VERSION 5.7 ;
  NOWIREEXTENSIONATPIN ON ;
  DIVIDERCHAR "/" ;
  BUSBITCHARS "[]" ;
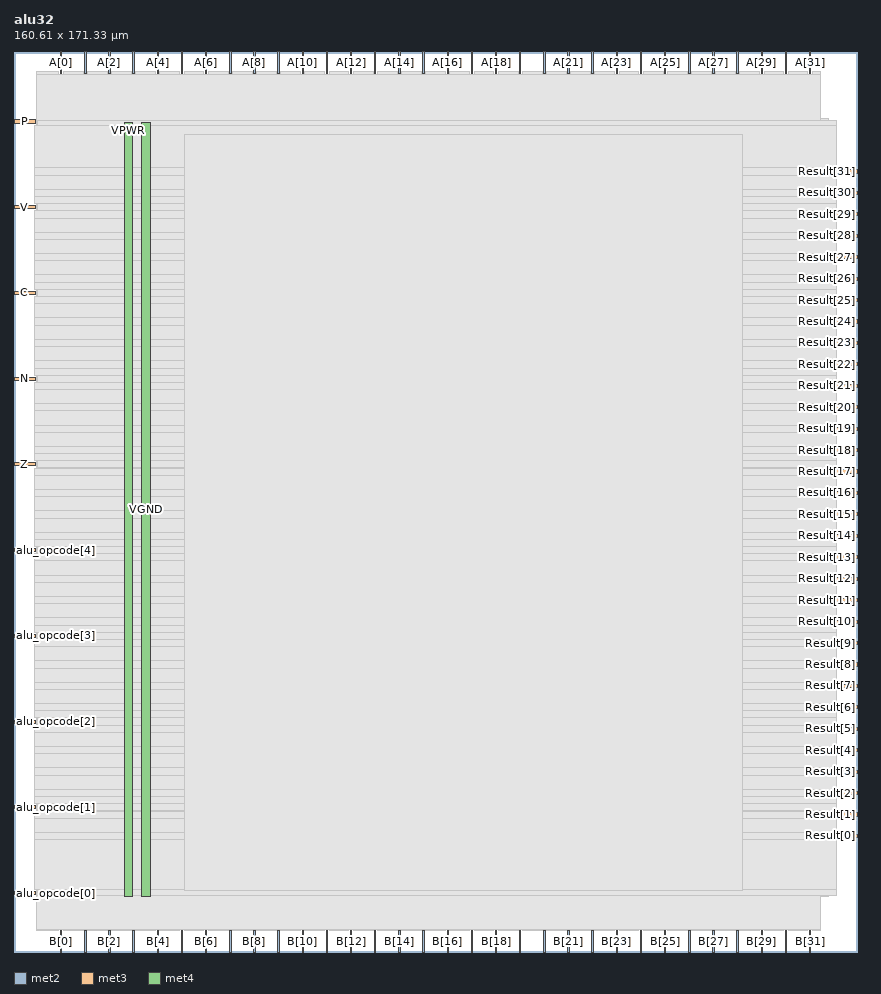
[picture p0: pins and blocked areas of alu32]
MACRO alu32
  CLASS BLOCK ;
  FOREIGN alu32 ;
  ORIGIN 0.000 0.000 ;
  SIZE 160.610 BY 171.330 ;
  PIN A[0]
    DIRECTION INPUT ;
    USE SIGNAL ;
    ANTENNAGATEAREA 0.213000 ;
    PORT
      LAYER met2 ;
        RECT 8.830 167.330 9.110 171.330 ;
    END
  END A[0]
  PIN A[10]
    DIRECTION INPUT ;
    USE SIGNAL ;
    ANTENNAGATEAREA 0.196500 ;
    PORT
      LAYER met2 ;
        RECT 54.830 167.330 55.110 171.330 ;
    END
  END A[10]
  PIN A[11]
    DIRECTION INPUT ;
    USE SIGNAL ;
    ANTENNAGATEAREA 0.196500 ;
    PORT
      LAYER met2 ;
        RECT 59.430 167.330 59.710 171.330 ;
    END
  END A[11]
  PIN A[12]
    DIRECTION INPUT ;
    USE SIGNAL ;
    ANTENNAGATEAREA 0.196500 ;
    PORT
      LAYER met2 ;
        RECT 64.030 167.330 64.310 171.330 ;
    END
  END A[12]
  PIN A[13]
    DIRECTION INPUT ;
    USE SIGNAL ;
    ANTENNAGATEAREA 0.196500 ;
    PORT
      LAYER met2 ;
        RECT 68.630 167.330 68.910 171.330 ;
    END
  END A[13]
  PIN A[14]
    DIRECTION INPUT ;
    USE SIGNAL ;
    ANTENNAGATEAREA 0.196500 ;
    PORT
      LAYER met2 ;
        RECT 73.230 167.330 73.510 171.330 ;
    END
  END A[14]
  PIN A[15]
    DIRECTION INPUT ;
    USE SIGNAL ;
    ANTENNAGATEAREA 0.196500 ;
    PORT
      LAYER met2 ;
        RECT 77.830 167.330 78.110 171.330 ;
    END
  END A[15]
  PIN A[16]
    DIRECTION INPUT ;
    USE SIGNAL ;
    ANTENNAGATEAREA 0.159000 ;
    PORT
      LAYER met2 ;
        RECT 82.430 167.330 82.710 171.330 ;
    END
  END A[16]
  PIN A[17]
    DIRECTION INPUT ;
    USE SIGNAL ;
    ANTENNAGATEAREA 0.159000 ;
    PORT
      LAYER met2 ;
        RECT 87.030 167.330 87.310 171.330 ;
    END
  END A[17]
  PIN A[18]
    DIRECTION INPUT ;
    USE SIGNAL ;
    ANTENNAGATEAREA 0.196500 ;
    PORT
      LAYER met2 ;
        RECT 91.630 167.330 91.910 171.330 ;
    END
  END A[18]
  PIN A[19]
    DIRECTION INPUT ;
    USE SIGNAL ;
    ANTENNAGATEAREA 0.196500 ;
    PORT
      LAYER met2 ;
        RECT 96.230 167.330 96.510 171.330 ;
    END
  END A[19]
  PIN A[1]
    DIRECTION INPUT ;
    USE SIGNAL ;
    ANTENNAGATEAREA 0.196500 ;
    PORT
      LAYER met2 ;
        RECT 13.430 167.330 13.710 171.330 ;
    END
  END A[1]
  PIN A[20]
    DIRECTION INPUT ;
    USE SIGNAL ;
    ANTENNAGATEAREA 0.196500 ;
    PORT
      LAYER met2 ;
        RECT 100.830 167.330 101.110 171.330 ;
    END
  END A[20]
  PIN A[21]
    DIRECTION INPUT ;
    USE SIGNAL ;
    ANTENNAGATEAREA 0.196500 ;
    PORT
      LAYER met2 ;
        RECT 105.430 167.330 105.710 171.330 ;
    END
  END A[21]
  PIN A[22]
    DIRECTION INPUT ;
    USE SIGNAL ;
    ANTENNAGATEAREA 0.196500 ;
    PORT
      LAYER met2 ;
        RECT 110.030 167.330 110.310 171.330 ;
    END
  END A[22]
  PIN A[23]
    DIRECTION INPUT ;
    USE SIGNAL ;
    ANTENNAGATEAREA 0.196500 ;
    PORT
      LAYER met2 ;
        RECT 114.630 167.330 114.910 171.330 ;
    END
  END A[23]
  PIN A[24]
    DIRECTION INPUT ;
    USE SIGNAL ;
    ANTENNAGATEAREA 0.196500 ;
    PORT
      LAYER met2 ;
        RECT 119.230 167.330 119.510 171.330 ;
    END
  END A[24]
  PIN A[25]
    DIRECTION INPUT ;
    USE SIGNAL ;
    ANTENNAGATEAREA 0.196500 ;
    PORT
      LAYER met2 ;
        RECT 123.830 167.330 124.110 171.330 ;
    END
  END A[25]
  PIN A[26]
    DIRECTION INPUT ;
    USE SIGNAL ;
    ANTENNAGATEAREA 0.196500 ;
    PORT
      LAYER met2 ;
        RECT 128.430 167.330 128.710 171.330 ;
    END
  END A[26]
  PIN A[27]
    DIRECTION INPUT ;
    USE SIGNAL ;
    ANTENNAGATEAREA 0.196500 ;
    PORT
      LAYER met2 ;
        RECT 133.030 167.330 133.310 171.330 ;
    END
  END A[27]
  PIN A[28]
    DIRECTION INPUT ;
    USE SIGNAL ;
    ANTENNAGATEAREA 0.196500 ;
    PORT
      LAYER met2 ;
        RECT 137.630 167.330 137.910 171.330 ;
    END
  END A[28]
  PIN A[29]
    DIRECTION INPUT ;
    USE SIGNAL ;
    ANTENNAGATEAREA 0.196500 ;
    PORT
      LAYER met2 ;
        RECT 142.230 167.330 142.510 171.330 ;
    END
  END A[29]
  PIN A[2]
    DIRECTION INPUT ;
    USE SIGNAL ;
    ANTENNAGATEAREA 0.196500 ;
    PORT
      LAYER met2 ;
        RECT 18.030 167.330 18.310 171.330 ;
    END
  END A[2]
  PIN A[30]
    DIRECTION INPUT ;
    USE SIGNAL ;
    ANTENNAGATEAREA 0.196500 ;
    PORT
      LAYER met2 ;
        RECT 146.830 167.330 147.110 171.330 ;
    END
  END A[30]
  PIN A[31]
    DIRECTION INPUT ;
    USE SIGNAL ;
    ANTENNAGATEAREA 0.196500 ;
    PORT
      LAYER met2 ;
        RECT 151.430 167.330 151.710 171.330 ;
    END
  END A[31]
  PIN A[3]
    DIRECTION INPUT ;
    USE SIGNAL ;
    ANTENNAGATEAREA 0.196500 ;
    PORT
      LAYER met2 ;
        RECT 22.630 167.330 22.910 171.330 ;
    END
  END A[3]
  PIN A[4]
    DIRECTION INPUT ;
    USE SIGNAL ;
    ANTENNAGATEAREA 0.196500 ;
    PORT
      LAYER met2 ;
        RECT 27.230 167.330 27.510 171.330 ;
    END
  END A[4]
  PIN A[5]
    DIRECTION INPUT ;
    USE SIGNAL ;
    ANTENNAGATEAREA 0.196500 ;
    PORT
      LAYER met2 ;
        RECT 31.830 167.330 32.110 171.330 ;
    END
  END A[5]
  PIN A[6]
    DIRECTION INPUT ;
    USE SIGNAL ;
    ANTENNAGATEAREA 0.196500 ;
    PORT
      LAYER met2 ;
        RECT 36.430 167.330 36.710 171.330 ;
    END
  END A[6]
  PIN A[7]
    DIRECTION INPUT ;
    USE SIGNAL ;
    ANTENNAGATEAREA 0.196500 ;
    PORT
      LAYER met2 ;
        RECT 41.030 167.330 41.310 171.330 ;
    END
  END A[7]
  PIN A[8]
    DIRECTION INPUT ;
    USE SIGNAL ;
    ANTENNAGATEAREA 0.196500 ;
    PORT
      LAYER met2 ;
        RECT 45.630 167.330 45.910 171.330 ;
    END
  END A[8]
  PIN A[9]
    DIRECTION INPUT ;
    USE SIGNAL ;
    ANTENNAGATEAREA 0.196500 ;
    PORT
      LAYER met2 ;
        RECT 50.230 167.330 50.510 171.330 ;
    END
  END A[9]
  PIN B[0]
    DIRECTION INPUT ;
    USE SIGNAL ;
    ANTENNAGATEAREA 0.247500 ;
    PORT
      LAYER met2 ;
        RECT 8.830 0.000 9.110 4.000 ;
    END
  END B[0]
  PIN B[10]
    DIRECTION INPUT ;
    USE SIGNAL ;
    ANTENNAGATEAREA 0.196500 ;
    PORT
      LAYER met2 ;
        RECT 54.830 0.000 55.110 4.000 ;
    END
  END B[10]
  PIN B[11]
    DIRECTION INPUT ;
    USE SIGNAL ;
    ANTENNAGATEAREA 0.126000 ;
    PORT
      LAYER met2 ;
        RECT 59.430 0.000 59.710 4.000 ;
    END
  END B[11]
  PIN B[12]
    DIRECTION INPUT ;
    USE SIGNAL ;
    ANTENNAGATEAREA 0.126000 ;
    PORT
      LAYER met2 ;
        RECT 64.030 0.000 64.310 4.000 ;
    END
  END B[12]
  PIN B[13]
    DIRECTION INPUT ;
    USE SIGNAL ;
    ANTENNAGATEAREA 0.196500 ;
    PORT
      LAYER met2 ;
        RECT 68.630 0.000 68.910 4.000 ;
    END
  END B[13]
  PIN B[14]
    DIRECTION INPUT ;
    USE SIGNAL ;
    ANTENNAGATEAREA 0.213000 ;
    PORT
      LAYER met2 ;
        RECT 73.230 0.000 73.510 4.000 ;
    END
  END B[14]
  PIN B[15]
    DIRECTION INPUT ;
    USE SIGNAL ;
    ANTENNAGATEAREA 0.196500 ;
    PORT
      LAYER met2 ;
        RECT 77.830 0.000 78.110 4.000 ;
    END
  END B[15]
  PIN B[16]
    DIRECTION INPUT ;
    USE SIGNAL ;
    ANTENNAGATEAREA 0.126000 ;
    PORT
      LAYER met2 ;
        RECT 82.430 0.000 82.710 4.000 ;
    END
  END B[16]
  PIN B[17]
    DIRECTION INPUT ;
    USE SIGNAL ;
    ANTENNAGATEAREA 0.196500 ;
    PORT
      LAYER met2 ;
        RECT 87.030 0.000 87.310 4.000 ;
    END
  END B[17]
  PIN B[18]
    DIRECTION INPUT ;
    USE SIGNAL ;
    ANTENNAGATEAREA 0.213000 ;
    PORT
      LAYER met2 ;
        RECT 91.630 0.000 91.910 4.000 ;
    END
  END B[18]
  PIN B[19]
    DIRECTION INPUT ;
    USE SIGNAL ;
    ANTENNAGATEAREA 0.213000 ;
    PORT
      LAYER met2 ;
        RECT 96.230 0.000 96.510 4.000 ;
    END
  END B[19]
  PIN B[1]
    DIRECTION INPUT ;
    USE SIGNAL ;
    ANTENNAGATEAREA 0.213000 ;
    PORT
      LAYER met2 ;
        RECT 13.430 0.000 13.710 4.000 ;
    END
  END B[1]
  PIN B[20]
    DIRECTION INPUT ;
    USE SIGNAL ;
    ANTENNAGATEAREA 0.196500 ;
    PORT
      LAYER met2 ;
        RECT 100.830 0.000 101.110 4.000 ;
    END
  END B[20]
  PIN B[21]
    DIRECTION INPUT ;
    USE SIGNAL ;
    ANTENNAGATEAREA 0.213000 ;
    PORT
      LAYER met2 ;
        RECT 105.430 0.000 105.710 4.000 ;
    END
  END B[21]
  PIN B[22]
    DIRECTION INPUT ;
    USE SIGNAL ;
    ANTENNAGATEAREA 0.126000 ;
    PORT
      LAYER met2 ;
        RECT 110.030 0.000 110.310 4.000 ;
    END
  END B[22]
  PIN B[23]
    DIRECTION INPUT ;
    USE SIGNAL ;
    ANTENNAGATEAREA 0.213000 ;
    PORT
      LAYER met2 ;
        RECT 114.630 0.000 114.910 4.000 ;
    END
  END B[23]
  PIN B[24]
    DIRECTION INPUT ;
    USE SIGNAL ;
    ANTENNAGATEAREA 0.213000 ;
    PORT
      LAYER met2 ;
        RECT 119.230 0.000 119.510 4.000 ;
    END
  END B[24]
  PIN B[25]
    DIRECTION INPUT ;
    USE SIGNAL ;
    ANTENNAGATEAREA 0.196500 ;
    PORT
      LAYER met2 ;
        RECT 123.830 0.000 124.110 4.000 ;
    END
  END B[25]
  PIN B[26]
    DIRECTION INPUT ;
    USE SIGNAL ;
    ANTENNAGATEAREA 0.126000 ;
    PORT
      LAYER met2 ;
        RECT 128.430 0.000 128.710 4.000 ;
    END
  END B[26]
  PIN B[27]
    DIRECTION INPUT ;
    USE SIGNAL ;
    ANTENNAGATEAREA 0.213000 ;
    PORT
      LAYER met2 ;
        RECT 133.030 0.000 133.310 4.000 ;
    END
  END B[27]
  PIN B[28]
    DIRECTION INPUT ;
    USE SIGNAL ;
    ANTENNAGATEAREA 0.213000 ;
    PORT
      LAYER met2 ;
        RECT 137.630 0.000 137.910 4.000 ;
    END
  END B[28]
  PIN B[29]
    DIRECTION INPUT ;
    USE SIGNAL ;
    ANTENNAGATEAREA 0.213000 ;
    PORT
      LAYER met2 ;
        RECT 142.230 0.000 142.510 4.000 ;
    END
  END B[29]
  PIN B[2]
    DIRECTION INPUT ;
    USE SIGNAL ;
    ANTENNAGATEAREA 0.196500 ;
    PORT
      LAYER met2 ;
        RECT 18.030 0.000 18.310 4.000 ;
    END
  END B[2]
  PIN B[30]
    DIRECTION INPUT ;
    USE SIGNAL ;
    ANTENNAGATEAREA 0.213000 ;
    PORT
      LAYER met2 ;
        RECT 146.830 0.000 147.110 4.000 ;
    END
  END B[30]
  PIN B[31]
    DIRECTION INPUT ;
    USE SIGNAL ;
    ANTENNAGATEAREA 0.213000 ;
    PORT
      LAYER met2 ;
        RECT 151.430 0.000 151.710 4.000 ;
    END
  END B[31]
  PIN B[3]
    DIRECTION INPUT ;
    USE SIGNAL ;
    ANTENNAGATEAREA 0.196500 ;
    PORT
      LAYER met2 ;
        RECT 22.630 0.000 22.910 4.000 ;
    END
  END B[3]
  PIN B[4]
    DIRECTION INPUT ;
    USE SIGNAL ;
    ANTENNAGATEAREA 0.196500 ;
    PORT
      LAYER met2 ;
        RECT 27.230 0.000 27.510 4.000 ;
    END
  END B[4]
  PIN B[5]
    DIRECTION INPUT ;
    USE SIGNAL ;
    ANTENNAGATEAREA 0.196500 ;
    PORT
      LAYER met2 ;
        RECT 31.830 0.000 32.110 4.000 ;
    END
  END B[5]
  PIN B[6]
    DIRECTION INPUT ;
    USE SIGNAL ;
    ANTENNAGATEAREA 0.126000 ;
    PORT
      LAYER met2 ;
        RECT 36.430 0.000 36.710 4.000 ;
    END
  END B[6]
  PIN B[7]
    DIRECTION INPUT ;
    USE SIGNAL ;
    ANTENNAGATEAREA 0.196500 ;
    PORT
      LAYER met2 ;
        RECT 41.030 0.000 41.310 4.000 ;
    END
  END B[7]
  PIN B[8]
    DIRECTION INPUT ;
    USE SIGNAL ;
    ANTENNAGATEAREA 0.196500 ;
    PORT
      LAYER met2 ;
        RECT 45.630 0.000 45.910 4.000 ;
    END
  END B[8]
  PIN B[9]
    DIRECTION INPUT ;
    USE SIGNAL ;
    ANTENNAGATEAREA 0.126000 ;
    PORT
      LAYER met2 ;
        RECT 50.230 0.000 50.510 4.000 ;
    END
  END B[9]
  PIN C
    DIRECTION OUTPUT ;
    USE SIGNAL ;
    ANTENNADIFFAREA 1.336500 ;
    PORT
      LAYER met3 ;
        RECT 0.000 125.160 4.000 125.760 ;
    END
  END C
  PIN N
    DIRECTION OUTPUT ;
    USE SIGNAL ;
    ANTENNADIFFAREA 0.445500 ;
    PORT
      LAYER met3 ;
        RECT 0.000 108.840 4.000 109.440 ;
    END
  END N
  PIN P
    DIRECTION OUTPUT ;
    USE SIGNAL ;
    ANTENNADIFFAREA 1.336500 ;
    PORT
      LAYER met3 ;
        RECT 0.000 157.800 4.000 158.400 ;
    END
  END P
  PIN Result[0]
    DIRECTION OUTPUT ;
    USE SIGNAL ;
    ANTENNADIFFAREA 1.336500 ;
    PORT
      LAYER met3 ;
        RECT 156.610 21.800 160.610 22.400 ;
    END
  END Result[0]
  PIN Result[10]
    DIRECTION OUTPUT ;
    USE SIGNAL ;
    ANTENNADIFFAREA 0.891000 ;
    PORT
      LAYER met3 ;
        RECT 156.610 62.600 160.610 63.200 ;
    END
  END Result[10]
  PIN Result[11]
    DIRECTION OUTPUT ;
    USE SIGNAL ;
    ANTENNADIFFAREA 1.336500 ;
    PORT
      LAYER met3 ;
        RECT 156.610 66.680 160.610 67.280 ;
    END
  END Result[11]
  PIN Result[12]
    DIRECTION OUTPUT ;
    USE SIGNAL ;
    ANTENNADIFFAREA 0.795200 ;
    PORT
      LAYER met3 ;
        RECT 156.610 70.760 160.610 71.360 ;
    END
  END Result[12]
  PIN Result[13]
    DIRECTION OUTPUT ;
    USE SIGNAL ;
    ANTENNADIFFAREA 1.336500 ;
    PORT
      LAYER met3 ;
        RECT 156.610 74.840 160.610 75.440 ;
    END
  END Result[13]
  PIN Result[14]
    DIRECTION OUTPUT ;
    USE SIGNAL ;
    ANTENNADIFFAREA 1.336500 ;
    PORT
      LAYER met3 ;
        RECT 156.610 78.920 160.610 79.520 ;
    END
  END Result[14]
  PIN Result[15]
    DIRECTION OUTPUT ;
    USE SIGNAL ;
    ANTENNADIFFAREA 1.336500 ;
    PORT
      LAYER met3 ;
        RECT 156.610 83.000 160.610 83.600 ;
    END
  END Result[15]
  PIN Result[16]
    DIRECTION OUTPUT ;
    USE SIGNAL ;
    ANTENNADIFFAREA 1.336500 ;
    PORT
      LAYER met3 ;
        RECT 156.610 87.080 160.610 87.680 ;
    END
  END Result[16]
  PIN Result[17]
    DIRECTION OUTPUT ;
    USE SIGNAL ;
    ANTENNADIFFAREA 1.336500 ;
    PORT
      LAYER met3 ;
        RECT 156.610 91.160 160.610 91.760 ;
    END
  END Result[17]
  PIN Result[18]
    DIRECTION OUTPUT ;
    USE SIGNAL ;
    ANTENNADIFFAREA 1.336500 ;
    PORT
      LAYER met3 ;
        RECT 156.610 95.240 160.610 95.840 ;
    END
  END Result[18]
  PIN Result[19]
    DIRECTION OUTPUT ;
    USE SIGNAL ;
    ANTENNADIFFAREA 1.336500 ;
    PORT
      LAYER met3 ;
        RECT 156.610 99.320 160.610 99.920 ;
    END
  END Result[19]
  PIN Result[1]
    DIRECTION OUTPUT ;
    USE SIGNAL ;
    ANTENNADIFFAREA 0.445500 ;
    PORT
      LAYER met3 ;
        RECT 156.610 25.880 160.610 26.480 ;
    END
  END Result[1]
  PIN Result[20]
    DIRECTION OUTPUT ;
    USE SIGNAL ;
    ANTENNADIFFAREA 1.336500 ;
    PORT
      LAYER met3 ;
        RECT 156.610 103.400 160.610 104.000 ;
    END
  END Result[20]
  PIN Result[21]
    DIRECTION OUTPUT ;
    USE SIGNAL ;
    ANTENNADIFFAREA 1.336500 ;
    PORT
      LAYER met3 ;
        RECT 156.610 107.480 160.610 108.080 ;
    END
  END Result[21]
  PIN Result[22]
    DIRECTION OUTPUT ;
    USE SIGNAL ;
    ANTENNADIFFAREA 1.336500 ;
    PORT
      LAYER met3 ;
        RECT 156.610 111.560 160.610 112.160 ;
    END
  END Result[22]
  PIN Result[23]
    DIRECTION OUTPUT ;
    USE SIGNAL ;
    ANTENNADIFFAREA 1.336500 ;
    PORT
      LAYER met3 ;
        RECT 156.610 115.640 160.610 116.240 ;
    END
  END Result[23]
  PIN Result[24]
    DIRECTION OUTPUT ;
    USE SIGNAL ;
    ANTENNADIFFAREA 1.782000 ;
    PORT
      LAYER met3 ;
        RECT 156.610 119.720 160.610 120.320 ;
    END
  END Result[24]
  PIN Result[25]
    DIRECTION OUTPUT ;
    USE SIGNAL ;
    ANTENNADIFFAREA 1.336500 ;
    PORT
      LAYER met3 ;
        RECT 156.610 123.800 160.610 124.400 ;
    END
  END Result[25]
  PIN Result[26]
    DIRECTION OUTPUT ;
    USE SIGNAL ;
    ANTENNADIFFAREA 1.782000 ;
    PORT
      LAYER met3 ;
        RECT 156.610 127.880 160.610 128.480 ;
    END
  END Result[26]
  PIN Result[27]
    DIRECTION OUTPUT ;
    USE SIGNAL ;
    ANTENNADIFFAREA 1.336500 ;
    PORT
      LAYER met3 ;
        RECT 156.610 131.960 160.610 132.560 ;
    END
  END Result[27]
  PIN Result[28]
    DIRECTION OUTPUT ;
    USE SIGNAL ;
    ANTENNADIFFAREA 1.336500 ;
    PORT
      LAYER met3 ;
        RECT 156.610 136.040 160.610 136.640 ;
    END
  END Result[28]
  PIN Result[29]
    DIRECTION OUTPUT ;
    USE SIGNAL ;
    ANTENNADIFFAREA 1.336500 ;
    PORT
      LAYER met3 ;
        RECT 156.610 140.120 160.610 140.720 ;
    END
  END Result[29]
  PIN Result[2]
    DIRECTION OUTPUT ;
    USE SIGNAL ;
    ANTENNADIFFAREA 1.336500 ;
    PORT
      LAYER met3 ;
        RECT 156.610 29.960 160.610 30.560 ;
    END
  END Result[2]
  PIN Result[30]
    DIRECTION OUTPUT ;
    USE SIGNAL ;
    ANTENNADIFFAREA 1.336500 ;
    PORT
      LAYER met3 ;
        RECT 156.610 144.200 160.610 144.800 ;
    END
  END Result[30]
  PIN Result[31]
    DIRECTION OUTPUT ;
    USE SIGNAL ;
    ANTENNADIFFAREA 1.336500 ;
    PORT
      LAYER met3 ;
        RECT 156.610 148.280 160.610 148.880 ;
    END
  END Result[31]
  PIN Result[3]
    DIRECTION OUTPUT ;
    USE SIGNAL ;
    ANTENNADIFFAREA 0.795200 ;
    PORT
      LAYER met3 ;
        RECT 156.610 34.040 160.610 34.640 ;
    END
  END Result[3]
  PIN Result[4]
    DIRECTION OUTPUT ;
    USE SIGNAL ;
    ANTENNADIFFAREA 0.445500 ;
    PORT
      LAYER met3 ;
        RECT 156.610 38.120 160.610 38.720 ;
    END
  END Result[4]
  PIN Result[5]
    DIRECTION OUTPUT ;
    USE SIGNAL ;
    ANTENNADIFFAREA 0.445500 ;
    PORT
      LAYER met3 ;
        RECT 156.610 42.200 160.610 42.800 ;
    END
  END Result[5]
  PIN Result[6]
    DIRECTION OUTPUT ;
    USE SIGNAL ;
    ANTENNADIFFAREA 0.445500 ;
    PORT
      LAYER met3 ;
        RECT 156.610 46.280 160.610 46.880 ;
    END
  END Result[6]
  PIN Result[7]
    DIRECTION OUTPUT ;
    USE SIGNAL ;
    ANTENNADIFFAREA 0.445500 ;
    PORT
      LAYER met3 ;
        RECT 156.610 50.360 160.610 50.960 ;
    END
  END Result[7]
  PIN Result[8]
    DIRECTION OUTPUT ;
    USE SIGNAL ;
    ANTENNADIFFAREA 0.795200 ;
    PORT
      LAYER met3 ;
        RECT 156.610 54.440 160.610 55.040 ;
    END
  END Result[8]
  PIN Result[9]
    DIRECTION OUTPUT ;
    USE SIGNAL ;
    ANTENNADIFFAREA 1.336500 ;
    PORT
      LAYER met3 ;
        RECT 156.610 58.520 160.610 59.120 ;
    END
  END Result[9]
  PIN V
    DIRECTION OUTPUT ;
    USE SIGNAL ;
    ANTENNADIFFAREA 1.336500 ;
    PORT
      LAYER met3 ;
        RECT 0.000 141.480 4.000 142.080 ;
    END
  END V
  PIN VGND
    DIRECTION INOUT ;
    USE GROUND ;
    PORT
      LAYER met4 ;
        RECT 24.340 10.640 25.940 158.000 ;
    END
  END VGND
  PIN VPWR
    DIRECTION INOUT ;
    USE POWER ;
    PORT
      LAYER met4 ;
        RECT 21.040 10.640 22.640 158.000 ;
    END
  END VPWR
  PIN Z
    DIRECTION OUTPUT ;
    USE SIGNAL ;
    ANTENNADIFFAREA 1.336500 ;
    PORT
      LAYER met3 ;
        RECT 0.000 92.520 4.000 93.120 ;
    END
  END Z
  PIN alu_opcode[0]
    DIRECTION INPUT ;
    USE SIGNAL ;
    ANTENNAGATEAREA 0.126000 ;
    PORT
      LAYER met3 ;
        RECT 0.000 10.920 4.000 11.520 ;
    END
  END alu_opcode[0]
  PIN alu_opcode[1]
    DIRECTION INPUT ;
    USE SIGNAL ;
    ANTENNAGATEAREA 0.159000 ;
    PORT
      LAYER met3 ;
        RECT 0.000 27.240 4.000 27.840 ;
    END
  END alu_opcode[1]
  PIN alu_opcode[2]
    DIRECTION INPUT ;
    USE SIGNAL ;
    ANTENNAGATEAREA 0.495000 ;
    PORT
      LAYER met3 ;
        RECT 0.000 43.560 4.000 44.160 ;
    END
  END alu_opcode[2]
  PIN alu_opcode[3]
    DIRECTION INPUT ;
    USE SIGNAL ;
    ANTENNAGATEAREA 0.742500 ;
    PORT
      LAYER met3 ;
        RECT 0.000 59.880 4.000 60.480 ;
    END
  END alu_opcode[3]
  PIN alu_opcode[4]
    DIRECTION INPUT ;
    USE SIGNAL ;
    ANTENNAGATEAREA 0.247500 ;
    PORT
      LAYER met3 ;
        RECT 0.000 76.200 4.000 76.800 ;
    END
  END alu_opcode[4]
  OBS
      LAYER nwell ;
        RECT 5.330 10.795 155.210 157.845 ;
      LAYER li1 ;
        RECT 5.520 10.795 155.020 157.845 ;
      LAYER met1 ;
        RECT 4.210 10.640 155.020 158.740 ;
      LAYER met2 ;
        RECT 4.230 167.050 8.550 167.690 ;
        RECT 9.390 167.050 13.150 167.690 ;
        RECT 13.990 167.050 17.750 167.690 ;
        RECT 18.590 167.050 22.350 167.690 ;
        RECT 23.190 167.050 26.950 167.690 ;
        RECT 27.790 167.050 31.550 167.690 ;
        RECT 32.390 167.050 36.150 167.690 ;
        RECT 36.990 167.050 40.750 167.690 ;
        RECT 41.590 167.050 45.350 167.690 ;
        RECT 46.190 167.050 49.950 167.690 ;
        RECT 50.790 167.050 54.550 167.690 ;
        RECT 55.390 167.050 59.150 167.690 ;
        RECT 59.990 167.050 63.750 167.690 ;
        RECT 64.590 167.050 68.350 167.690 ;
        RECT 69.190 167.050 72.950 167.690 ;
        RECT 73.790 167.050 77.550 167.690 ;
        RECT 78.390 167.050 82.150 167.690 ;
        RECT 82.990 167.050 86.750 167.690 ;
        RECT 87.590 167.050 91.350 167.690 ;
        RECT 92.190 167.050 95.950 167.690 ;
        RECT 96.790 167.050 100.550 167.690 ;
        RECT 101.390 167.050 105.150 167.690 ;
        RECT 105.990 167.050 109.750 167.690 ;
        RECT 110.590 167.050 114.350 167.690 ;
        RECT 115.190 167.050 118.950 167.690 ;
        RECT 119.790 167.050 123.550 167.690 ;
        RECT 124.390 167.050 128.150 167.690 ;
        RECT 128.990 167.050 132.750 167.690 ;
        RECT 133.590 167.050 137.350 167.690 ;
        RECT 138.190 167.050 141.950 167.690 ;
        RECT 142.790 167.050 146.550 167.690 ;
        RECT 147.390 167.050 151.150 167.690 ;
        RECT 151.990 167.050 153.550 167.690 ;
        RECT 4.230 4.280 153.550 167.050 ;
        RECT 4.230 4.000 8.550 4.280 ;
        RECT 9.390 4.000 13.150 4.280 ;
        RECT 13.990 4.000 17.750 4.280 ;
        RECT 18.590 4.000 22.350 4.280 ;
        RECT 23.190 4.000 26.950 4.280 ;
        RECT 27.790 4.000 31.550 4.280 ;
        RECT 32.390 4.000 36.150 4.280 ;
        RECT 36.990 4.000 40.750 4.280 ;
        RECT 41.590 4.000 45.350 4.280 ;
        RECT 46.190 4.000 49.950 4.280 ;
        RECT 50.790 4.000 54.550 4.280 ;
        RECT 55.390 4.000 59.150 4.280 ;
        RECT 59.990 4.000 63.750 4.280 ;
        RECT 64.590 4.000 68.350 4.280 ;
        RECT 69.190 4.000 72.950 4.280 ;
        RECT 73.790 4.000 77.550 4.280 ;
        RECT 78.390 4.000 82.150 4.280 ;
        RECT 82.990 4.000 86.750 4.280 ;
        RECT 87.590 4.000 91.350 4.280 ;
        RECT 92.190 4.000 95.950 4.280 ;
        RECT 96.790 4.000 100.550 4.280 ;
        RECT 101.390 4.000 105.150 4.280 ;
        RECT 105.990 4.000 109.750 4.280 ;
        RECT 110.590 4.000 114.350 4.280 ;
        RECT 115.190 4.000 118.950 4.280 ;
        RECT 119.790 4.000 123.550 4.280 ;
        RECT 124.390 4.000 128.150 4.280 ;
        RECT 128.990 4.000 132.750 4.280 ;
        RECT 133.590 4.000 137.350 4.280 ;
        RECT 138.190 4.000 141.950 4.280 ;
        RECT 142.790 4.000 146.550 4.280 ;
        RECT 147.390 4.000 151.150 4.280 ;
        RECT 151.990 4.000 153.550 4.280 ;
      LAYER met3 ;
        RECT 4.400 157.400 156.610 158.250 ;
        RECT 3.990 149.280 156.610 157.400 ;
        RECT 3.990 147.880 156.210 149.280 ;
        RECT 3.990 145.200 156.610 147.880 ;
        RECT 3.990 143.800 156.210 145.200 ;
        RECT 3.990 142.480 156.610 143.800 ;
        RECT 4.400 141.120 156.610 142.480 ;
        RECT 4.400 141.080 156.210 141.120 ;
        RECT 3.990 139.720 156.210 141.080 ;
        RECT 3.990 137.040 156.610 139.720 ;
        RECT 3.990 135.640 156.210 137.040 ;
        RECT 3.990 132.960 156.610 135.640 ;
        RECT 3.990 131.560 156.210 132.960 ;
        RECT 3.990 128.880 156.610 131.560 ;
        RECT 3.990 127.480 156.210 128.880 ;
        RECT 3.990 126.160 156.610 127.480 ;
        RECT 4.400 124.800 156.610 126.160 ;
        RECT 4.400 124.760 156.210 124.800 ;
        RECT 3.990 123.400 156.210 124.760 ;
        RECT 3.990 120.720 156.610 123.400 ;
        RECT 3.990 119.320 156.210 120.720 ;
        RECT 3.990 116.640 156.610 119.320 ;
        RECT 3.990 115.240 156.210 116.640 ;
        RECT 3.990 112.560 156.610 115.240 ;
        RECT 3.990 111.160 156.210 112.560 ;
        RECT 3.990 109.840 156.610 111.160 ;
        RECT 4.400 108.480 156.610 109.840 ;
        RECT 4.400 108.440 156.210 108.480 ;
        RECT 3.990 107.080 156.210 108.440 ;
        RECT 3.990 104.400 156.610 107.080 ;
        RECT 3.990 103.000 156.210 104.400 ;
        RECT 3.990 100.320 156.610 103.000 ;
        RECT 3.990 98.920 156.210 100.320 ;
        RECT 3.990 96.240 156.610 98.920 ;
        RECT 3.990 94.840 156.210 96.240 ;
        RECT 3.990 93.520 156.610 94.840 ;
        RECT 4.400 92.160 156.610 93.520 ;
        RECT 4.400 92.120 156.210 92.160 ;
        RECT 3.990 90.760 156.210 92.120 ;
        RECT 3.990 88.080 156.610 90.760 ;
        RECT 3.990 86.680 156.210 88.080 ;
        RECT 3.990 84.000 156.610 86.680 ;
        RECT 3.990 82.600 156.210 84.000 ;
        RECT 3.990 79.920 156.610 82.600 ;
        RECT 3.990 78.520 156.210 79.920 ;
        RECT 3.990 77.200 156.610 78.520 ;
        RECT 4.400 75.840 156.610 77.200 ;
        RECT 4.400 75.800 156.210 75.840 ;
        RECT 3.990 74.440 156.210 75.800 ;
        RECT 3.990 71.760 156.610 74.440 ;
        RECT 3.990 70.360 156.210 71.760 ;
        RECT 3.990 67.680 156.610 70.360 ;
        RECT 3.990 66.280 156.210 67.680 ;
        RECT 3.990 63.600 156.610 66.280 ;
        RECT 3.990 62.200 156.210 63.600 ;
        RECT 3.990 60.880 156.610 62.200 ;
        RECT 4.400 59.520 156.610 60.880 ;
        RECT 4.400 59.480 156.210 59.520 ;
        RECT 3.990 58.120 156.210 59.480 ;
        RECT 3.990 55.440 156.610 58.120 ;
        RECT 3.990 54.040 156.210 55.440 ;
        RECT 3.990 51.360 156.610 54.040 ;
        RECT 3.990 49.960 156.210 51.360 ;
        RECT 3.990 47.280 156.610 49.960 ;
        RECT 3.990 45.880 156.210 47.280 ;
        RECT 3.990 44.560 156.610 45.880 ;
        RECT 4.400 43.200 156.610 44.560 ;
        RECT 4.400 43.160 156.210 43.200 ;
        RECT 3.990 41.800 156.210 43.160 ;
        RECT 3.990 39.120 156.610 41.800 ;
        RECT 3.990 37.720 156.210 39.120 ;
        RECT 3.990 35.040 156.610 37.720 ;
        RECT 3.990 33.640 156.210 35.040 ;
        RECT 3.990 30.960 156.610 33.640 ;
        RECT 3.990 29.560 156.210 30.960 ;
        RECT 3.990 28.240 156.610 29.560 ;
        RECT 4.400 26.880 156.610 28.240 ;
        RECT 4.400 26.840 156.210 26.880 ;
        RECT 3.990 25.480 156.210 26.840 ;
        RECT 3.990 22.800 156.610 25.480 ;
        RECT 3.990 21.400 156.210 22.800 ;
        RECT 3.990 11.920 156.610 21.400 ;
        RECT 4.400 10.715 156.610 11.920 ;
      LAYER met4 ;
        RECT 32.495 11.735 138.625 155.545 ;
  END
END alu32
END LIBRARY

